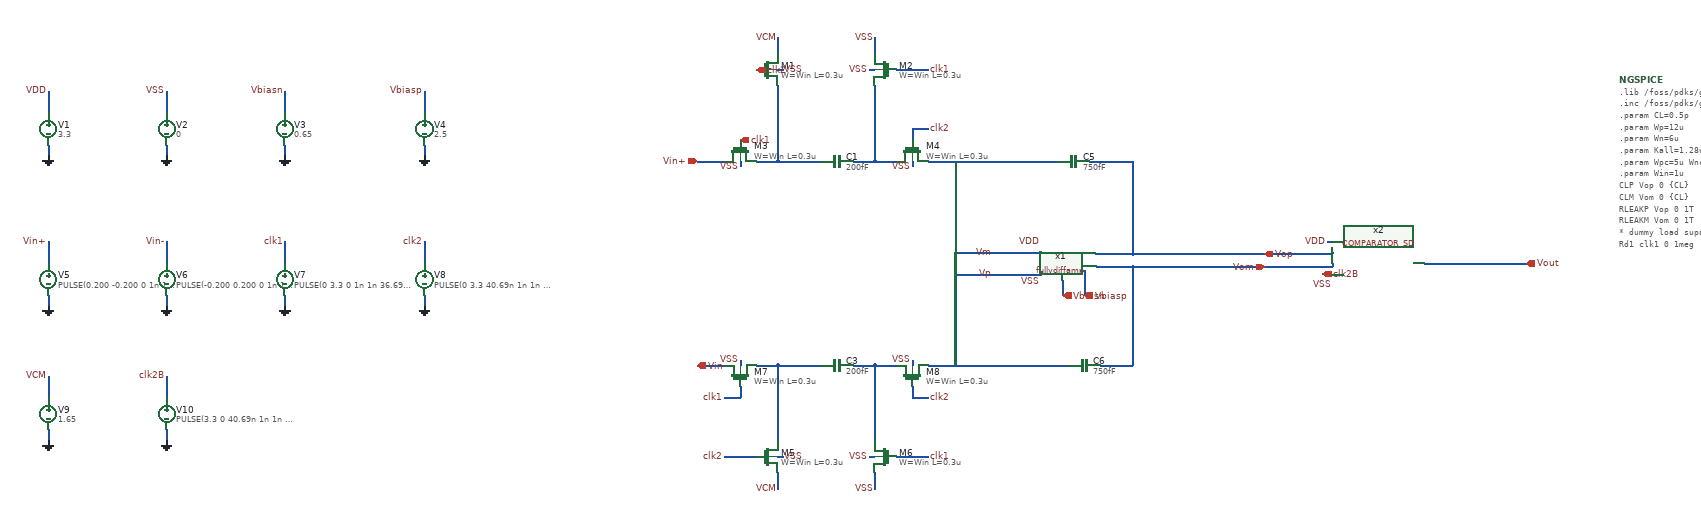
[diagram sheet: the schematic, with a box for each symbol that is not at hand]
v {xschem version=3.4.8RC file_version=1.3}
G {}
K {}
V {}
S {}
F {}
E {}
N 347.5 -1320 347.5 -1180 {lab=#net1}
N 307.5 -1180 347.5 -1180 {lab=#net1}
N 347.5 -1180 427.5 -1180 {lab=#net1}
N 487.5 -1180 527.5 -1180 {lab=#net2}
N 527.5 -1320 527.5 -1180 {lab=#net2}
N 527.5 -1180 567.5 -1180 {lab=#net2}
N 627.5 -1180 667.5 -1180 {lab=Vm}
N 227.5 -1180 247.5 -1180 {lab=Vin+}
N 197.5 -1180 227.5 -1180 {lab=Vin+}
N 597.5 -1240 597.5 -1220 {lab=clk2}
N 597.5 -1240 627.5 -1240 {lab=clk2}
N 567.5 -1350 627.5 -1350 {lab=clk1}
N 527.5 -1410 527.5 -1380 {lab=VSS}
N 347.5 -1410 347.5 -1380 {lab=VCM}
N 347.5 -800 347.5 -660 {lab=#net3}
N 307.5 -800 347.5 -800 {lab=#net3}
N 347.5 -800 427.5 -800 {lab=#net3}
N 487.5 -800 527.5 -800 {lab=#net4}
N 527.5 -800 527.5 -660 {lab=#net4}
N 527.5 -800 567.5 -800 {lab=#net4}
N 627.5 -800 667.5 -800 {lab=Vp}
N 227.5 -800 247.5 -800 {lab=Vin-}
N 197.5 -800 227.5 -800 {lab=Vin-}
N 277.5 -760 277.5 -740 {lab=clk1}
N 247.5 -740 277.5 -740 {lab=clk1}
N 247.5 -630 307.5 -630 {lab=clk2}
N 597.5 -760 597.5 -740 {lab=clk2}
N 597.5 -740 627.5 -740 {lab=clk2}
N 567.5 -630 627.5 -630 {lab=clk1}
N 527.5 -600 527.5 -570 {lab=VSS}
N 347.5 -600 347.5 -570 {lab=VCM}
N 347.5 -1350 357.5 -1350 {lab=VSS}
N 517.5 -1350 527.5 -1350 {lab=VSS}
N 277.5 -1180 277.5 -1170 {lab=VSS}
N 597.5 -1180 597.5 -1170 {lab=VSS}
N 277.5 -810 277.5 -800 {lab=VSS}
N 597.5 -810 597.5 -800 {lab=VSS}
N 347.5 -630 357.5 -630 {lab=VSS}
N 517.5 -630 527.5 -630 {lab=VSS}
N 667.5 -1180 867.5 -1180 {lab=Vm}
N 667.5 -800 887.5 -800 {lab=Vp}
N 677.5 -1180 677.5 -1010 {lab=Vm}
N 677.5 -1010 837.5 -1010 {lab=Vm}
N 677.5 -970 677.5 -800 {lab=Vp}
N 677.5 -970 837.5 -970 {lab=Vp}
N 837.5 -975 837.5 -970 {lab=Vp}
N 927.5 -1180 997.5 -1180 {lab=Vop}
N 947.5 -800 1007.5 -800 {lab=Vom}
N 940 -983.75 1007.5 -983.75 {lab=Vom}
N 938.75 -1007.5 1006.25 -1007.5 {lab=Vop}
N 997.5 -1180 1007.5 -1180 {lab=Vop}
N 1006.25 -1007.5 1007.5 -1007.5 {lab=Vop}
N 1007.5 -1180 1007.5 -1007.5 {lab=Vop}
N 1007.5 -983.75 1007.5 -800 {lab=Vom}
N 910 -977.5 917.5 -977.5 {lab=Vbiasp}
N 917.5 -977.5 917.5 -930 {lab=Vbiasp}
N 877.5 -957.5 877.5 -930 {lab=Vbiasn}
N 1007.5 -1007.5 1050 -1007.5 {lab=Vop}
N 1007.5 -983.75 1050 -983.75 {lab=Vom}
N 1230 -1007.5 1380 -1007.5 {lab=Vop}
N 1380 -1010 1380 -1007.5 {lab=Vop}
N 1230 -983.75 1380 -983.75 {lab=Vom}
N 1380 -990 1380 -983.75 {lab=Vom}
N 1550 -990 1720 -990 {lab=Vout}
N 1720 -990 1740 -990 {lab=Vout}
N 1052.5 -1007.5 1100 -1007.5 {lab=Vop}
N 1052.5 -983.75 1100 -983.75 {lab=Vom}
N 1050 -1007.5 1052.5 -1007.5 {lab=Vop}
N 1050 -983.75 1052.5 -983.75 {lab=Vom}
N -1010 -1310 -1010 -1270 {lab=VDD}
N -1010 -1210 -1010 -1190 {lab=0}
N -790 -1310 -790 -1270 {lab=VSS}
N -790 -1210 -790 -1190 {lab=0}
N -570 -1310 -570 -1270 {lab=Vbiasn}
N -570 -1210 -570 -1190 {lab=0}
N -310 -1310 -310 -1270 {lab=Vbiasp}
N -310 -1210 -310 -1190 {lab=0}
N -1010 -1030 -1010 -990 {lab=Vin+}
N -1010 -930 -1010 -910 {lab=0}
N -790 -1030 -790 -990 {lab=Vin-}
N -790 -930 -790 -910 {lab=0}
N -570 -1030 -570 -990 {lab=clk1}
N -570 -930 -570 -910 {lab=0}
N -310 -1030 -310 -990 {lab=clk2}
N -310 -930 -310 -910 {lab=0}
N -1010 -780 -1010 -740 {lab=VCM}
N -1010 -680 -1010 -660 {lab=0}
N -790 -780 -790 -740 {lab=clk2B}
N -790 -680 -790 -660 {lab=0}
N 1100 -1007.5 1230 -1007.5 {lab=Vop}
N 1100 -983.75 1230 -983.75 {lab=Vom}
N 1360.9375 -970.3125 1380 -970 {lab=clk2B}
N 1369.6875 -1030 1380 -1030 {lab=VDD}
C {symbols/nfet_03v3.sym} 327.5 -1350 2 1 {name=M1
L=0.3u
W=Win
nf=1
m=1
ad="'int((nf+1)/2) * W/nf * 0.18u'"
pd="'2*int((nf+1)/2) * (W/nf + 0.18u)'"
as="'int((nf+2)/2) * W/nf * 0.18u'"
ps="'2*int((nf+2)/2) * (W/nf + 0.18u)'"
nrd="'0.18u / W'" nrs="'0.18u / W'"
sa=0 sb=0 sd=0
model=nfet_03v3
spiceprefix=X
}
C {symbols/nfet_03v3.sym} 547.5 -1350 2 0 {name=M2
L=0.3u
W=Win
nf=1
m=1
ad="'int((nf+1)/2) * W/nf * 0.18u'"
pd="'2*int((nf+1)/2) * (W/nf + 0.18u)'"
as="'int((nf+2)/2) * W/nf * 0.18u'"
ps="'2*int((nf+2)/2) * (W/nf + 0.18u)'"
nrd="'0.18u / W'" nrs="'0.18u / W'"
sa=0 sb=0 sd=0
model=nfet_03v3
spiceprefix=X
}
C {symbols/nfet_03v3.sym} 277.5 -1200 3 1 {name=M3
L=0.3u
W=Win
nf=1
m=1
ad="'int((nf+1)/2) * W/nf * 0.18u'"
pd="'2*int((nf+1)/2) * (W/nf + 0.18u)'"
as="'int((nf+2)/2) * W/nf * 0.18u'"
ps="'2*int((nf+2)/2) * (W/nf + 0.18u)'"
nrd="'0.18u / W'" nrs="'0.18u / W'"
sa=0 sb=0 sd=0
model=nfet_03v3
spiceprefix=X
}
C {symbols/nfet_03v3.sym} 597.5 -1200 3 1 {name=M4
L=0.3u
W=Win
nf=1
m=1
ad="'int((nf+1)/2) * W/nf * 0.18u'"
pd="'2*int((nf+1)/2) * (W/nf + 0.18u)'"
as="'int((nf+2)/2) * W/nf * 0.18u'"
ps="'2*int((nf+2)/2) * (W/nf + 0.18u)'"
nrd="'0.18u / W'" nrs="'0.18u / W'"
sa=0 sb=0 sd=0
model=nfet_03v3
spiceprefix=X
}
C {capa.sym} 457.5 -1180 1 1 {name=C1
m=1
value=200fF
footprint=1206
device="ceramic capacitor"}
C {ipin.sym} 197.5 -1180 0 0 {name=p3 lab=Vin+}
C {lab_pin.sym} 627.5 -1350 2 0 {name=p1 sig_type=std_logic lab=clk1}
C {lab_pin.sym} 627.5 -1240 2 0 {name=p5 sig_type=std_logic lab=clk2}
C {symbols/nfet_03v3.sym} 327.5 -630 0 0 {name=M5
L=0.3u
W=Win
nf=1
m=1
ad="'int((nf+1)/2) * W/nf * 0.18u'"
pd="'2*int((nf+1)/2) * (W/nf + 0.18u)'"
as="'int((nf+2)/2) * W/nf * 0.18u'"
ps="'2*int((nf+2)/2) * (W/nf + 0.18u)'"
nrd="'0.18u / W'" nrs="'0.18u / W'"
sa=0 sb=0 sd=0
model=nfet_03v3
spiceprefix=X
}
C {symbols/nfet_03v3.sym} 547.5 -630 0 1 {name=M6
L=0.3u
W=Win
nf=1
m=1
ad="'int((nf+1)/2) * W/nf * 0.18u'"
pd="'2*int((nf+1)/2) * (W/nf + 0.18u)'"
as="'int((nf+2)/2) * W/nf * 0.18u'"
ps="'2*int((nf+2)/2) * (W/nf + 0.18u)'"
nrd="'0.18u / W'" nrs="'0.18u / W'"
sa=0 sb=0 sd=0
model=nfet_03v3
spiceprefix=X
}
C {symbols/nfet_03v3.sym} 277.5 -780 3 0 {name=M7
L=0.3u
W=Win
nf=1
m=1
ad="'int((nf+1)/2) * W/nf * 0.18u'"
pd="'2*int((nf+1)/2) * (W/nf + 0.18u)'"
as="'int((nf+2)/2) * W/nf * 0.18u'"
ps="'2*int((nf+2)/2) * (W/nf + 0.18u)'"
nrd="'0.18u / W'" nrs="'0.18u / W'"
sa=0 sb=0 sd=0
model=nfet_03v3
spiceprefix=X
}
C {symbols/nfet_03v3.sym} 597.5 -780 3 0 {name=M8
L=0.3u
W=Win
nf=1
m=1
ad="'int((nf+1)/2) * W/nf * 0.18u'"
pd="'2*int((nf+1)/2) * (W/nf + 0.18u)'"
as="'int((nf+2)/2) * W/nf * 0.18u'"
ps="'2*int((nf+2)/2) * (W/nf + 0.18u)'"
nrd="'0.18u / W'" nrs="'0.18u / W'"
sa=0 sb=0 sd=0
model=nfet_03v3
spiceprefix=X
}
C {capa.sym} 457.5 -800 1 0 {name=C3
m=1
value=200fF
footprint=1206
device="ceramic capacitor"}
C {ipin.sym} 197.5 -800 2 1 {name=p6 lab=Vin-}
C {lab_pin.sym} 627.5 -630 0 1 {name=p7 sig_type=std_logic lab=clk1}
C {lab_pin.sym} 247.5 -740 2 1 {name=p8 sig_type=std_logic lab=clk1}
C {lab_pin.sym} 247.5 -630 2 1 {name=p9 sig_type=std_logic lab=clk2}
C {lab_pin.sym} 627.5 -740 0 1 {name=p10 sig_type=std_logic lab=clk2}
C {lab_pin.sym} 357.5 -1350 2 0 {name=p13 sig_type=std_logic lab=VSS}
C {lab_pin.sym} 517.5 -1350 0 0 {name=p14 sig_type=std_logic lab=VSS}
C {lab_pin.sym} 277.5 -1170 3 0 {name=p15 sig_type=std_logic lab=VSS}
C {lab_pin.sym} 597.5 -1170 3 0 {name=p16 sig_type=std_logic lab=VSS}
C {lab_pin.sym} 277.5 -810 1 0 {name=p17 sig_type=std_logic lab=VSS}
C {lab_pin.sym} 597.5 -810 1 0 {name=p18 sig_type=std_logic lab=VSS}
C {lab_pin.sym} 357.5 -630 2 0 {name=p19 sig_type=std_logic lab=VSS}
C {lab_pin.sym} 517.5 -630 0 0 {name=p20 sig_type=std_logic lab=VSS}
C {capa.sym} 897.5 -1180 3 0 {name=C5
m=1
value=750fF
footprint=1206
device="ceramic capacitor"}
C {capa.sym} 917.5 -800 3 0 {name=C6
m=1
value=750fF
footprint=1206
device="ceramic capacitor"}
C {opin.sym} 1252.5 -1007.5 3 0 {name=p11 lab=Vop}
C {opin.sym} 1253.75 -983.75 3 1 {name=p12 lab=Vom}
C {lab_pin.sym} 837.5 -955 0 0 {name=p23 sig_type=std_logic lab=VSS}
C {lab_pin.sym} 837.5 -1030 0 0 {name=p24 sig_type=std_logic lab=VDD}
C {lab_pin.sym} 527.5 -570 3 0 {name=p38 sig_type=std_logic lab=VSS}
C {lab_pin.sym} 527.5 -1410 1 0 {name=p39 sig_type=std_logic lab=VSS}
C {ipin.sym} 277.5 -1220 3 1 {name=p41 lab=clk1}
C {ipin.sym} 307.5 -1350 2 1 {name=p2 lab=clk2}
C {ipin.sym} 877.5 -930 1 1 {name=p4 lab=Vbiasn}
C {ipin.sym} 917.5 -930 1 1 {name=p42 lab=Vbiasp}
C {lab_pin.sym} 747.5 -1010 1 0 {name=p33 sig_type=std_logic lab=Vm}
C {lab_pin.sym} 747.5 -970 3 0 {name=p34 sig_type=std_logic lab=Vp}
C {fully_differential_amplifier/fullydiffamp.sym} 897.5 -905 0 0 {name=x1}
C {lab_pin.sym} 1369.6875 -1030 0 0 {name=p46 sig_type=std_logic lab=VDD}
C {lab_pin.sym} 1380 -950 0 0 {name=p47 sig_type=std_logic lab=VSS}
C {opin.sym} 1740 -990 0 0 {name=p52 lab=Vout}
C {ipin.sym} 1360.9375 -970.3125 2 1 {name=p57 lab=clk2B}
C {lab_pin.sym} 347.5 -1410 1 0 {name=p36 sig_type=std_logic lab=VCM}
C {lab_pin.sym} 347.5 -570 3 0 {name=p21 sig_type=std_logic lab=VCM}
C {vsource.sym} -1010 -1240 0 0 {name=V1 value=3.3 savecurrent=false}
C {gnd.sym} -1010 -1190 0 0 {name=l5 lab=0}
C {vsource.sym} -790 -1240 0 0 {name=V2 value=0 savecurrent=false}
C {gnd.sym} -790 -1190 0 0 {name=l6 lab=0}
C {vsource.sym} -570 -1240 0 0 {name=V3 value=0.65 savecurrent=false}
C {gnd.sym} -570 -1190 0 0 {name=l7 lab=0}
C {vsource.sym} -310 -1240 0 0 {name=V4 value=2.5 savecurrent=false}
C {gnd.sym} -310 -1190 0 0 {name=l8 lab=0}
C {vsource.sym} -1010 -960 0 0 {name=V5 value="PULSE(0.200 -0.200 0 1n 1n 5u 10u)" savecurrent=false}
C {gnd.sym} -1010 -910 0 0 {name=l9 lab=0}
C {vsource.sym} -790 -960 0 0 {name=V6 value="PULSE(-0.200 0.200 0 1n 1n 5u 10u)" savecurrent=false}
C {gnd.sym} -790 -910 0 0 {name=l10 lab=0}
C {vsource.sym} -570 -960 0 0 {name=V7 value="PULSE(0 3.3 0 1n 1n 36.69n 81.38n)" savecurrent=false}
C {gnd.sym} -570 -910 0 0 {name=l11 lab=0}
C {vsource.sym} -310 -960 0 0 {name=V8 value="PULSE(0 3.3 40.69n 1n 1n 36.69n 81.38n)" savecurrent=false}
C {gnd.sym} -310 -910 0 0 {name=l12 lab=0}
C {lab_pin.sym} -1010 -1310 1 0 {name=p25 sig_type=std_logic lab=VDD}
C {lab_pin.sym} -790 -1310 1 0 {name=p26 sig_type=std_logic lab=VSS
}
C {lab_pin.sym} -570 -1310 1 0 {name=p27 sig_type=std_logic lab=Vbiasn
}
C {lab_pin.sym} -310 -1310 1 0 {name=p28 sig_type=std_logic lab=Vbiasp
}
C {lab_pin.sym} -1010 -1030 1 0 {name=p29 sig_type=std_logic lab=Vin+}
C {lab_pin.sym} -790 -1030 1 0 {name=p30 sig_type=std_logic lab=Vin-}
C {lab_pin.sym} -570 -1030 1 0 {name=p31 sig_type=std_logic lab=clk1}
C {lab_pin.sym} -310 -1030 1 0 {name=p32 sig_type=std_logic lab=clk2}
C {vsource.sym} -1010 -710 0 0 {name=V9 value=1.65 savecurrent=false}
C {gnd.sym} -1010 -660 0 0 {name=l1 lab=0}
C {lab_pin.sym} -1010 -780 1 0 {name=p35 sig_type=std_logic lab=VCM}
C {devices/code_shown.sym} 1913.125 -1331.25 0 0 {name=NGSPICE only_toplevel=true
value="
.lib /foss/pdks/gf180mcuD/libs.tech/ngspice/sm141064.ngspice typical
.inc /foss/pdks/gf180mcuD/libs.tech/ngspice/design.ngspice

.param CL=0.5p
.param Wp=12u
.param Wn=6u
.param Kall=1.28u
.param Wpc=5u Wnc=2.5u Wsc=2*Wp Lc=0.3u
.param Win=1u
CLP Vop 0 \{CL\}
CLM Vom 0 \{CL\}
RLEAKP Vop 0 1T
RLEAKM Vom 0 1T

* dummy load supaya tiap node punya DC path ke ground
Rd1 clk1  0 1meg
Rd2 clk2  0 1meg

.control
set color0=white
set color1=black
tran 2n 200u
let vicm_ota = (v(Vp)+v(Vm))/2
let vid_ota  = v(Vp)-v(Vm)
* --- window ala paper ---
plot v(clk1) v(clk2)          $ window 1: non-overlapping clocks
plot v(Vin+) v(Vin-)          $ window 2: input diferensial
plot v(Vop) v(Vom)            $ window 3: output OTA (single-ended)
plot v(Vop)-v(Vom) v(Vout)           $ window 4: output integrator (diferensial) -> segitiga
plot v(Vp) v(Vm)
plot vicm_ota
plot vid_ota
.endc
.end
"}
C {vsource.sym} -790 -710 0 0 {name=V10 value="PULSE(3.3 0 40.69n 1n 1n 36.69n 81.38n)" savecurrent=false}
C {gnd.sym} -790 -660 0 0 {name=l2 lab=0}
C {lab_pin.sym} -790 -780 1 0 {name=p22 sig_type=std_logic lab=clk2B}
C {latched_comparator/COMPARATOR_SD.sym} 1360 -830 0 0 {name=x2}
